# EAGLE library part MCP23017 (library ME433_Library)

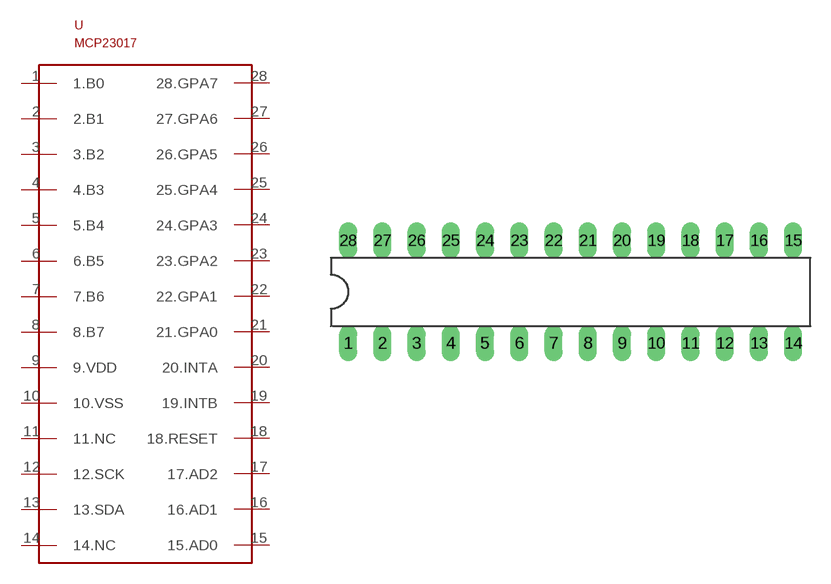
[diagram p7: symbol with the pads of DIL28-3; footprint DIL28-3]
Designator prefix -

## MCP23017  [DIL28-3]
1  1.B0
2  2.B1
3  3.B2
4  4.B3
5  5.B4
6  6.B5
7  7.B6
8  8.B7
9  9.VDD
10  10.VSS
11  11.NC
12  12.SCK
13  13.SDA
14  14.NC
15  15.AD0
16  16.AD1
17  17.AD2
18  18.RESET
19  19.INTB
20  20.INTA
21  21.GPA0
22  22.GPA1
23  23.GPA2
24  24.GPA3
25  25.GPA4
26  26.GPA5
27  27.GPA6
28  28.GPA7

## Footprint DIL28-3 (pad centres in mm)
Dual In Line package type P
drill 0.813 long: 1 -16.51,-3.81; 2 -13.97,-3.81; 3 -11.43,-3.81; 4 -8.89,-3.81; 5 -6.35,-3.81; 6 -3.81,-3.81; 7 -1.27,-3.81; 8 1.27,-3.81; 9 3.81,-3.81; 10 6.35,-3.81; 11 8.89,-3.81; 12 11.43,-3.81; 13 13.97,-3.81; 14 16.51,-3.81; 15 16.51,3.81; 16 13.97,3.81; 17 11.43,3.81; 18 8.89,3.81; 19 6.35,3.81; 20 3.81,3.81; 21 1.27,3.81; 22 -1.27,3.81; 23 -3.81,3.81; 24 -6.35,3.81; 25 -8.89,3.81; 26 -11.43,3.81; 27 -13.97,3.81; 28 -16.51,3.81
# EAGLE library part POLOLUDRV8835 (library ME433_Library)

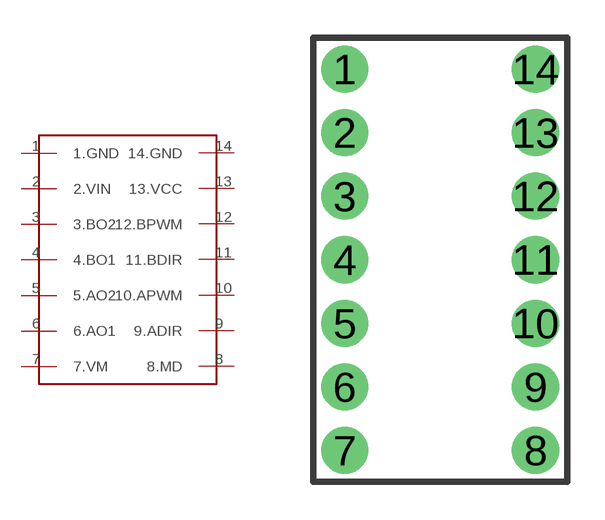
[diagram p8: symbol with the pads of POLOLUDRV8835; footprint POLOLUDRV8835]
Designator prefix -

## POLOLUDRV8835  [POLOLUDRV8835]
1  1.GND
2  2.VIN
3  3.BO2
4  4.BO1
5  5.AO2
6  6.AO1
7  7.VM
8  8.MD
9  9.ADIR
10  10.APWM
11  11.BDIR
12  12.BPWM
13  13.VCC
14  14.GND

## Footprint POLOLUDRV8835 (pad centres in mm)
drill 1.016 pad 1.88: 1 -3.81,7.62; 2 -3.81,5.08; 3 -3.81,2.54; 4 -3.81,0; 5 -3.81,-2.54; 6 -3.81,-5.08; 7 -3.81,-7.62; 8 3.81,-7.62; 9 3.81,-5.08; 10 3.81,-2.54; 11 3.81,0; 12 3.81,2.54; 13 3.81,5.08; 14 3.81,7.62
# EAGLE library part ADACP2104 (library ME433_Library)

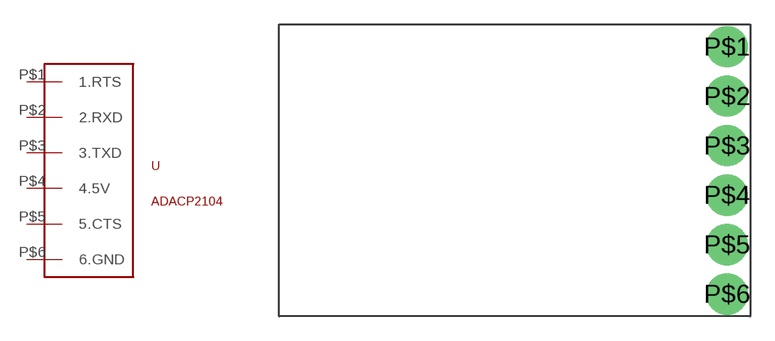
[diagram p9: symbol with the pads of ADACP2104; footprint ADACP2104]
Designator prefix -

## ADACP2104  [ADACP2104]
P$1  1.RTS
P$2  2.RXD
P$3  3.TXD
P$4  4.5V
P$5  5.CTS
P$6  6.GND

## Footprint ADACP2104 (pad centres in mm)
drill 1.27 pad 2.54: P$1 13.081,7.62; P$2 13.081,4.572; P$3 13.081,1.524; P$4 13.081,-1.524; P$5 13.081,-4.572; P$6 13.081,-7.62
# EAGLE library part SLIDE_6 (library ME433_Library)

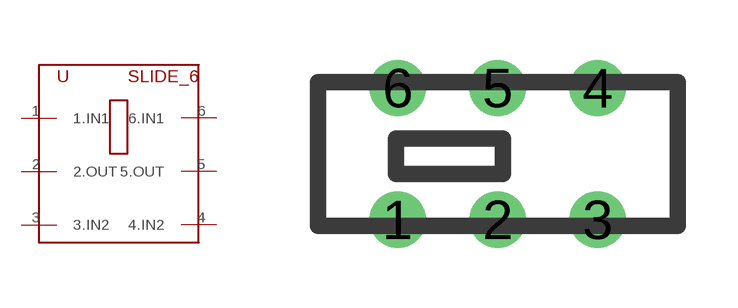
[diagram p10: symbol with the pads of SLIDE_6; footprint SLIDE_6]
Designator prefix -

## SLIDE_6  [SLIDE_6]
1  1.IN1
2  2.OUT
3  3.IN2
4  4.IN2
5  5.OUT
6  6.IN1

## Footprint SLIDE_6 (pad centres in mm)
drill 0.9: 1 -2.5,-1.65; 2 0,-1.65; 3 2.5,-1.65; 4 2.5,1.65; 5 0,1.65; 6 -2.5,1.65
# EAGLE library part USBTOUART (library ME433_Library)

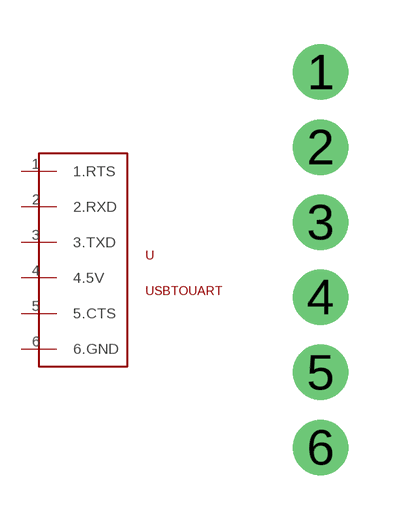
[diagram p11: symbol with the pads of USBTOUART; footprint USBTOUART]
Designator prefix -

## USBTOUART  [USBTOUART]
1  1.RTS
2  2.RXD
3  3.TXD
4  4.5V
5  5.CTS
6  6.GND

## Footprint USBTOUART (pad centres in mm)
drill 1.016 pad 1.88: 1 2.54,6.35; 2 2.54,3.81; 3 2.54,1.27; 4 2.54,-1.27; 5 2.54,-3.81; 6 2.54,-6.35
